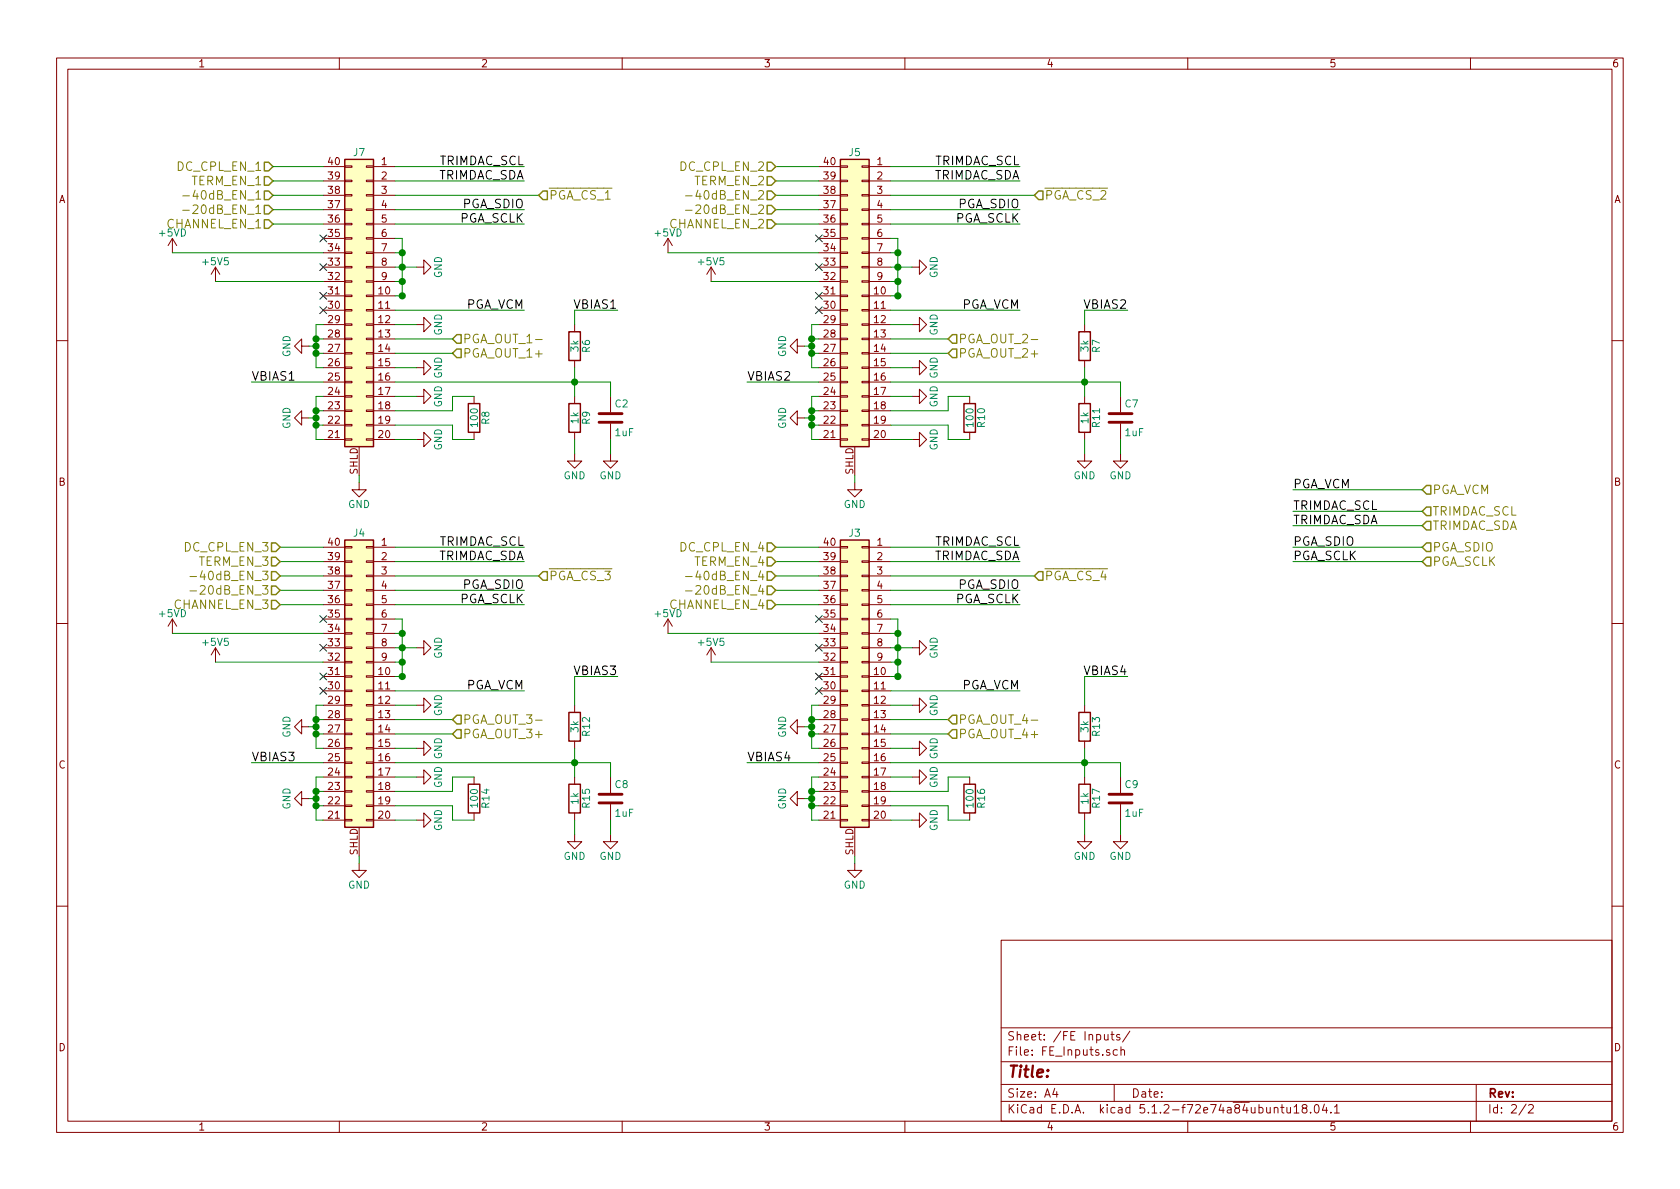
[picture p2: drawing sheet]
<svg xmlns="http://www.w3.org/2000/svg" width="297mm" height="210mm" viewBox="0 0 297 210" stroke-linecap="round" stroke-linejoin="round" font-family="sans-serif">
<defs><g id="words">
<text font-size="2.8" fill="#840000" x="178" y="190.5">Title:</text>
<g font-size="2.1">
<text x="77.5" y="29.2">TRIMDAC_SCL</text>
<text x="165.1" y="29.2">TRIMDAC_SCL</text>
<text x="77.3" y="31.7">TRIMDAC_SDA</text>
<text x="164.9" y="31.7">TRIMDAC_SDA</text>
<text x="81.2" y="39.4">PGA_SCLK</text>
<text x="81.7" y="36.8">PGA_SDIO</text>
<text x="168.8" y="39.4">PGA_SCLK</text>
<text x="169.4" y="36.8">PGA_SDIO</text>
<text x="82.2" y="54.6">PGA_VCM</text>
<text x="101.5" y="54.6">VBIAS1</text>
<text x="169.8" y="54.6">PGA_VCM</text>
<text x="191.7" y="54.6">VBIAS2</text>
<text x="44.4" y="67.3">VBIAS1</text>
<text x="132.1" y="67.3">VBIAS2</text>
<text x="228.6" y="86.4">PGA_VCM</text>
<text x="228.6" y="92.7">TRIMDAC_SDA</text>
<text x="228.6" y="90.2">TRIMDAC_SCL</text>
<text x="77.3" y="99.1">TRIMDAC_SDA</text>
<text x="77.5" y="96.5">TRIMDAC_SCL</text>
<text x="164.9" y="99.1">TRIMDAC_SDA</text>
<text x="165.1" y="96.5">TRIMDAC_SCL</text>
<text x="228.6" y="99.1">PGA_SCLK</text>
<text x="228.6" y="96.5">PGA_SDIO</text>
<text x="81.2" y="106.7">PGA_SCLK</text>
<text x="81.7" y="104.1">PGA_SDIO</text>
<text x="168.8" y="106.7">PGA_SCLK</text>
<text x="169.4" y="104.1">PGA_SDIO</text>
<text x="101.5" y="119.4">VBIAS3</text>
<text x="191.7" y="119.4">VBIAS4</text>
<text x="82.2" y="121.9">PGA_VCM</text>
<text x="169.8" y="121.9">PGA_VCM</text>
<text x="44.4" y="134.6">VBIAS3</text>
<text x="132.1" y="134.6">VBIAS4</text>
</g>
<g font-size="2.1" fill="#848400">
<text x="31.5" y="30.2">DC_CPL_EN_1</text>
<text x="34" y="32.8">TERM_EN_1</text>
<text x="34.1" y="35.3">-40dB_EN_1</text>
<text x="97" y="35.3">PGA_CS_1</text>
<text x="120.4" y="30.2">DC_CPL_EN_2</text>
<text x="122.9" y="32.8">TERM_EN_2</text>
<text x="123" y="35.3">-40dB_EN_2</text>
<text x="184.7" y="35.3">PGA_CS_2</text>
<text x="29.6" y="40.4">CHANNEL_EN_1</text>
<text x="34.1" y="37.8">-20dB_EN_1</text>
<text x="118.5" y="40.4">CHANNEL_EN_2</text>
<text x="123" y="37.8">-20dB_EN_2</text>
<text x="81.8" y="60.7">PGA_OUT_1-</text>
<text x="81.8" y="63.2">PGA_OUT_1+</text>
<text x="169.4" y="60.7">PGA_OUT_2-</text>
<text x="169.4" y="63.2">PGA_OUT_2+</text>
<text x="253.2" y="87.4">PGA_VCM</text>
<text x="253.2" y="91.2">TRIMDAC_SCL</text>
<text x="253.2" y="93.7">TRIMDAC_SDA</text>
<text x="32.8" y="97.5">DC_CPL_EN_3</text>
<text x="35.3" y="100.1">TERM_EN_3</text>
<text x="120.4" y="97.5">DC_CPL_EN_4</text>
<text x="122.9" y="100.1">TERM_EN_4</text>
<text x="253.2" y="97.5">PGA_SDIO</text>
<text x="253.2" y="100.1">PGA_SCLK</text>
<text x="30.9" y="107.7">CHANNEL_EN_3</text>
<text x="35.4" y="105.2">-20dB_EN_3</text>
<text x="35.4" y="102.6">-40dB_EN_3</text>
<text x="97" y="102.6">PGA_CS_3</text>
<text x="118.5" y="107.7">CHANNEL_EN_4</text>
<text x="123" y="105.2">-20dB_EN_4</text>
<text x="123" y="102.6">-40dB_EN_4</text>
<text x="184.7" y="102.6">PGA_CS_4</text>
<text x="81.8" y="128">PGA_OUT_3-</text>
<text x="81.8" y="130.6">PGA_OUT_3+</text>
<text x="169.4" y="128">PGA_OUT_4-</text>
<text x="169.4" y="130.6">PGA_OUT_4+</text>
</g>
<g font-size="2.1" fill="#840000">
<text x="178" y="184">Sheet: /FE Inputs/</text>
<text x="178" y="186.7">File: FE_Inputs.sch</text>
<text x="178" y="196.9">KiCad E.D.A. kicad 5.1.2-f72e74a84ubuntu18.04.1</text>
<text x="178" y="194.1">Size: A4</text>
<text x="200" y="194.1">Date:</text>
<text x="263" y="194.1">Rev:</text>
<text x="263" y="196.9">Id: 2/2</text>
</g>
<g font-size="1.8" fill="#840000">
<text x="35" y="11.9">1</text>
<text x="85" y="11.9">2</text>
<text x="135" y="11.9">3</text>
<text x="185" y="11.9">4</text>
<text x="235" y="11.9">5</text>
<text x="285" y="11.9">6</text>
<text x="58.1" y="29.2">40</text>
<text x="67.5" y="29.2">1</text>
<text x="145.7" y="29.2">40</text>
<text x="155.1" y="29.2">1</text>
<text x="10.4" y="35.9">A</text>
<text x="58.1" y="34.3">38</text>
<text x="58.1" y="31.7">39</text>
<text x="67.5" y="31.7">2</text>
<text x="67.5" y="34.3">3</text>
<text x="145.7" y="34.3">38</text>
<text x="145.7" y="31.7">39</text>
<text x="155.1" y="31.7">2</text>
<text x="155.1" y="34.3">3</text>
<text x="285.4" y="35.9">A</text>
<text x="58.1" y="41.9">35</text>
<text x="58.1" y="39.4">36</text>
<text x="58.1" y="36.8">37</text>
<text x="67.5" y="36.8">4</text>
<text x="67.5" y="39.4">5</text>
<text x="67.5" y="41.9">6</text>
<text x="145.7" y="41.9">35</text>
<text x="145.7" y="39.4">36</text>
<text x="145.7" y="36.8">37</text>
<text x="155.1" y="36.8">4</text>
<text x="155.1" y="39.4">5</text>
<text x="155.1" y="41.9">6</text>
<text x="58.1" y="47">33</text>
<text x="58.1" y="44.4">34</text>
<text x="67.5" y="44.4">7</text>
<text x="67.5" y="47">8</text>
<text x="145.7" y="47">33</text>
<text x="145.7" y="44.4">34</text>
<text x="155.1" y="44.4">7</text>
<text x="155.1" y="47">8</text>
<text x="58.1" y="52.1">31</text>
<text x="58.1" y="49.5">32</text>
<text x="67" y="52.1">10</text>
<text x="67.5" y="49.5">9</text>
<text x="145.7" y="52.1">31</text>
<text x="145.7" y="49.5">32</text>
<text x="154.6" y="52.1">10</text>
<text x="155.1" y="49.5">9</text>
<text x="58.1" y="59.7">28</text>
<text x="58.1" y="57.1">29</text>
<text x="58.1" y="54.6">30</text>
<text x="67" y="54.6">11</text>
<text x="67" y="57.1">12</text>
<text x="67" y="59.7">13</text>
<text x="145.7" y="59.7">28</text>
<text x="145.7" y="57.1">29</text>
<text x="145.7" y="54.6">30</text>
<text x="154.6" y="54.6">11</text>
<text x="154.6" y="57.1">12</text>
<text x="154.6" y="59.7">13</text>
<text x="58.1" y="64.8">26</text>
<text x="58.1" y="62.2">27</text>
<text x="67" y="62.2">14</text>
<text x="67" y="64.8">15</text>
<text x="145.7" y="64.8">26</text>
<text x="145.7" y="62.2">27</text>
<text x="154.6" y="62.2">14</text>
<text x="154.6" y="64.8">15</text>
<text x="58.1" y="69.8">24</text>
<text x="58.1" y="67.3">25</text>
<text x="67" y="67.3">16</text>
<text x="67" y="69.8">17</text>
<text x="145.7" y="69.8">24</text>
<text x="145.7" y="67.3">25</text>
<text x="154.6" y="67.3">16</text>
<text x="154.6" y="69.8">17</text>
<text x="58.1" y="77.5">21</text>
<text x="58.1" y="74.9">22</text>
<text x="58.1" y="72.4">23</text>
<text x="67" y="72.4">18</text>
<text x="67" y="74.9">19</text>
<text x="67" y="77.5">20</text>
<text x="145.7" y="77.5">21</text>
<text x="145.7" y="74.9">22</text>
<text x="145.7" y="72.4">23</text>
<text x="154.6" y="72.4">18</text>
<text x="154.6" y="74.9">19</text>
<text x="154.6" y="77.5">20</text>
<text x="63.2" y="83.9" transform="rotate(-90 63.2 83.9)">SHLD</text>
<text x="150.9" y="83.9" transform="rotate(-90 150.9 83.9)">SHLD</text>
<text x="10.4" y="85.9">B</text>
<text x="285.4" y="85.9">B</text>
<text x="58.1" y="101.6">38</text>
<text x="58.1" y="99.1">39</text>
<text x="58.1" y="96.5">40</text>
<text x="67.5" y="96.5">1</text>
<text x="67.5" y="99.1">2</text>
<text x="67.5" y="101.6">3</text>
<text x="145.7" y="101.6">38</text>
<text x="145.7" y="99.1">39</text>
<text x="145.7" y="96.5">40</text>
<text x="155.1" y="96.5">1</text>
<text x="155.1" y="99.1">2</text>
<text x="155.1" y="101.6">3</text>
<text x="58.1" y="106.7">36</text>
<text x="58.1" y="104.1">37</text>
<text x="67.5" y="104.1">4</text>
<text x="67.5" y="106.7">5</text>
<text x="145.7" y="106.7">36</text>
<text x="145.7" y="104.1">37</text>
<text x="155.1" y="104.1">4</text>
<text x="155.1" y="106.7">5</text>
<text x="58.1" y="111.8">34</text>
<text x="58.1" y="109.2">35</text>
<text x="67.5" y="109.2">6</text>
<text x="67.5" y="111.8">7</text>
<text x="145.7" y="111.8">34</text>
<text x="145.7" y="109.2">35</text>
<text x="155.1" y="109.2">6</text>
<text x="155.1" y="111.8">7</text>
<text x="58.1" y="119.4">31</text>
<text x="58.1" y="116.8">32</text>
<text x="58.1" y="114.3">33</text>
<text x="67" y="119.4">10</text>
<text x="67.5" y="114.3">8</text>
<text x="67.5" y="116.8">9</text>
<text x="145.7" y="119.4">31</text>
<text x="145.7" y="116.8">32</text>
<text x="145.7" y="114.3">33</text>
<text x="154.6" y="119.4">10</text>
<text x="155.1" y="114.3">8</text>
<text x="155.1" y="116.8">9</text>
<text x="58.1" y="124.5">29</text>
<text x="58.1" y="121.9">30</text>
<text x="67" y="121.9">11</text>
<text x="67" y="124.5">12</text>
<text x="145.7" y="124.5">29</text>
<text x="145.7" y="121.9">30</text>
<text x="154.6" y="121.9">11</text>
<text x="154.6" y="124.5">12</text>
<text x="58.1" y="129.5">27</text>
<text x="58.1" y="127">28</text>
<text x="67" y="127">13</text>
<text x="67" y="129.5">14</text>
<text x="145.7" y="129.5">27</text>
<text x="145.7" y="127">28</text>
<text x="154.6" y="127">13</text>
<text x="154.6" y="129.5">14</text>
<text x="10.4" y="135.9">C</text>
<text x="58.1" y="137.2">24</text>
<text x="58.1" y="134.6">25</text>
<text x="58.1" y="132.1">26</text>
<text x="67" y="132.1">15</text>
<text x="67" y="134.6">16</text>
<text x="67" y="137.2">17</text>
<text x="145.7" y="137.2">24</text>
<text x="145.7" y="134.6">25</text>
<text x="145.7" y="132.1">26</text>
<text x="154.6" y="132.1">15</text>
<text x="154.6" y="134.6">16</text>
<text x="154.6" y="137.2">17</text>
<text x="285.4" y="135.9">C</text>
<text x="58.1" y="142.2">22</text>
<text x="58.1" y="139.7">23</text>
<text x="67" y="139.7">18</text>
<text x="67" y="142.2">19</text>
<text x="145.7" y="142.2">22</text>
<text x="145.7" y="139.7">23</text>
<text x="154.6" y="139.7">18</text>
<text x="154.6" y="142.2">19</text>
<text x="58.1" y="144.8">21</text>
<text x="67" y="144.8">20</text>
<text x="145.7" y="144.8">21</text>
<text x="154.6" y="144.8">20</text>
<text x="63.2" y="151.3" transform="rotate(-90 63.2 151.3)">SHLD</text>
<text x="150.9" y="151.3" transform="rotate(-90 150.9 151.3)">SHLD</text>
<text x="10.4" y="185.9">D</text>
<text x="285.4" y="185.9">D</text>
<text x="35" y="199.9">1</text>
<text x="85" y="199.9">2</text>
<text x="135" y="199.9">3</text>
<text x="185" y="199.9">4</text>
<text x="235" y="199.9">5</text>
<text x="285" y="199.9">6</text>
</g>
<g font-size="1.8" fill="#008484">
<text x="62.5" y="27.6">J7</text>
<text x="150.2" y="27.6">J5</text>
<text x="28.2" y="41.8">+5VD</text>
<text x="115.9" y="41.8">+5VD</text>
<text x="36" y="46.9">+5V5</text>
<text x="123.6" y="46.9">+5V5</text>
<text x="78.2" y="49.2" transform="rotate(-90 78.2 49.2)">GND</text>
<text x="165.8" y="49.2" transform="rotate(-90 165.8 49.2)">GND</text>
<text x="78.2" y="59.4" transform="rotate(-90 78.2 59.4)">GND</text>
<text x="165.8" y="59.4" transform="rotate(-90 165.8 59.4)">GND</text>
<text x="51.4" y="63.2" transform="rotate(-90 51.4 63.2)">GND</text>
<text x="102.3" y="62.2" transform="rotate(-90 102.3 62.2)">3k</text>
<text x="104.3" y="62.3" transform="rotate(-90 104.3 62.3)">R6</text>
<text x="139" y="63.2" transform="rotate(-90 139 63.2)">GND</text>
<text x="192.5" y="62.2" transform="rotate(-90 192.5 62.2)">3k</text>
<text x="194.5" y="62.3" transform="rotate(-90 194.5 62.3)">R7</text>
<text x="78.2" y="67" transform="rotate(-90 78.2 67)">GND</text>
<text x="165.8" y="67" transform="rotate(-90 165.8 67)">GND</text>
<text x="51.4" y="75.9" transform="rotate(-90 51.4 75.9)">GND</text>
<text x="78.2" y="72.1" transform="rotate(-90 78.2 72.1)">GND</text>
<text x="84.5" y="75.4" transform="rotate(-90 84.5 75.4)">100</text>
<text x="86.5" y="75" transform="rotate(-90 86.5 75)">R8</text>
<text x="102.3" y="74.9" transform="rotate(-90 102.3 74.9)">1k</text>
<text x="104.3" y="75" transform="rotate(-90 104.3 75)">R9</text>
<text x="108.8" y="72.1">C2</text>
<text x="108.8" y="77.1">1uF</text>
<text x="139" y="75.9" transform="rotate(-90 139 75.9)">GND</text>
<text x="165.8" y="72.1" transform="rotate(-90 165.8 72.1)">GND</text>
<text x="172.1" y="75.4" transform="rotate(-90 172.1 75.4)">100</text>
<text x="174.2" y="75.5" transform="rotate(-90 174.2 75.5)">R10</text>
<text x="192.5" y="74.9" transform="rotate(-90 192.5 74.9)">1k</text>
<text x="194.5" y="75.5" transform="rotate(-90 194.5 75.5)">R11</text>
<text x="199" y="72.1">C7</text>
<text x="199" y="77.1">1uF</text>
<text x="78.2" y="79.7" transform="rotate(-90 78.2 79.7)">GND</text>
<text x="165.8" y="79.7" transform="rotate(-90 165.8 79.7)">GND</text>
<text x="61.5" y="89.8">GND</text>
<text x="99.6" y="84.8">GND</text>
<text x="106" y="84.8">GND</text>
<text x="149.2" y="89.8">GND</text>
<text x="189.8" y="84.8">GND</text>
<text x="196.2" y="84.8">GND</text>
<text x="62.5" y="94.9">J4</text>
<text x="150.2" y="94.9">J3</text>
<text x="28.2" y="109.1">+5VD</text>
<text x="115.9" y="109.1">+5VD</text>
<text x="36" y="114.2">+5V5</text>
<text x="78.2" y="116.5" transform="rotate(-90 78.2 116.5)">GND</text>
<text x="123.6" y="114.2">+5V5</text>
<text x="165.8" y="116.5" transform="rotate(-90 165.8 116.5)">GND</text>
<text x="51.4" y="130.5" transform="rotate(-90 51.4 130.5)">GND</text>
<text x="78.2" y="126.7" transform="rotate(-90 78.2 126.7)">GND</text>
<text x="102.3" y="129.5" transform="rotate(-90 102.3 129.5)">3k</text>
<text x="104.3" y="130.1" transform="rotate(-90 104.3 130.1)">R12</text>
<text x="139" y="130.5" transform="rotate(-90 139 130.5)">GND</text>
<text x="165.8" y="126.7" transform="rotate(-90 165.8 126.7)">GND</text>
<text x="192.5" y="129.5" transform="rotate(-90 192.5 129.5)">3k</text>
<text x="194.5" y="130.1" transform="rotate(-90 194.5 130.1)">R13</text>
<text x="78.2" y="134.3" transform="rotate(-90 78.2 134.3)">GND</text>
<text x="165.8" y="134.3" transform="rotate(-90 165.8 134.3)">GND</text>
<text x="51.4" y="143.2" transform="rotate(-90 51.4 143.2)">GND</text>
<text x="78.2" y="139.4" transform="rotate(-90 78.2 139.4)">GND</text>
<text x="84.5" y="142.7" transform="rotate(-90 84.5 142.7)">100</text>
<text x="86.5" y="142.8" transform="rotate(-90 86.5 142.8)">R14</text>
<text x="102.3" y="142.2" transform="rotate(-90 102.3 142.2)">1k</text>
<text x="104.3" y="142.8" transform="rotate(-90 104.3 142.8)">R15</text>
<text x="108.8" y="139.4">C8</text>
<text x="139" y="143.2" transform="rotate(-90 139 143.2)">GND</text>
<text x="165.8" y="139.4" transform="rotate(-90 165.8 139.4)">GND</text>
<text x="172.1" y="142.7" transform="rotate(-90 172.1 142.7)">100</text>
<text x="174.2" y="142.8" transform="rotate(-90 174.2 142.8)">R16</text>
<text x="192.5" y="142.2" transform="rotate(-90 192.5 142.2)">1k</text>
<text x="194.5" y="142.8" transform="rotate(-90 194.5 142.8)">R17</text>
<text x="199" y="139.4">C9</text>
<text x="78.2" y="147" transform="rotate(-90 78.2 147)">GND</text>
<text x="108.8" y="144.4">1uF</text>
<text x="165.8" y="147" transform="rotate(-90 165.8 147)">GND</text>
<text x="199" y="144.4">1uF</text>
<text x="99.6" y="152.1">GND</text>
<text x="106" y="152.1">GND</text>
<text x="189.8" y="152.1">GND</text>
<text x="196.2" y="152.1">GND</text>
<text x="61.5" y="157.1">GND</text>
<text x="149.2" y="157.1">GND</text>
</g>
</g></defs>
<g fill="none" stroke="#840000" stroke-width=".18">
<path d="M10 10.3h277v189.9h-277zM12 12.2h273v186.1h-273zM60 10.3v1.9M110 10.3v1.9M160 10.3v1.9M210 10.3v1.9M260 10.3v1.9M57.1 29.5h3.9M57.1 32h3.9M57.1 34.5h3.9M57.1 39.6h3.9M57.1 37.1h3.9"/>
<path d="M61 39.5h1.2v.2h-1.2zM61 37h1.2v.2h-1.2zM61 34.4h1.2v.3h-1.2zM61 31.9h1.2v.2h-1.2zM61 29.3h1.2v.3h-1.2zM64.8 39.5h1.2v.2h-1.2zM64.8 37h1.2v.2h-1.2zM64.8 34.4h1.2v.3h-1.2zM64.8 31.9h1.2v.2h-1.2zM64.8 29.3h1.2v.3h-1.2zM66 29.5h3.8M66 32h3.8"/>
<path d="M66 34.5h3.8M66 39.6h3.8M66 37.1h3.8M144.8 29.5h3.8M144.8 32h3.8M144.8 34.5h3.8M144.8 39.6h3.8M144.8 37.1h3.8M148.6 39.5h1.3v.2h-1.3zM148.6 37h1.3v.2h-1.3zM148.6 34.4h1.3v.3h-1.3zM148.6 31.9h1.3v.2h-1.3z"/>
<path d="M148.6 29.3h1.3v.3h-1.3zM152.4 39.5h1.3v.2h-1.3zM152.4 37h1.3v.2h-1.3zM152.4 34.4h1.3v.3h-1.3zM152.4 31.9h1.3v.2h-1.3zM152.4 29.3h1.3v.3h-1.3zM153.7 29.5h3.8M153.7 32h3.8M153.7 34.5h3.8M153.7 39.6h3.8M153.7 37.1h3.8M30.5 42.2l.7 1.2"/>
<path d="M30.5 42.2v2.5M30.5 42.2l-.8 1.2M38.1 47.2l.8 1.3M38.1 47.2v2.6M38.1 47.2l-.8 1.3M57.1 52.3h3.9M57.1 54.9h3.9M57.1 57.4h3.9M57.1 59.9h3.9M57.1 49.8h3.9M57.1 47.2h3.9M57.1 44.7h3.9"/>
<path d="M57.1 42.2h3.9M61 59.8h1.2v.3h-1.2zM61 57.3h1.2v.2h-1.2zM61 54.7h1.2v.3h-1.2zM61 52.2h1.2v.2h-1.2zM61 49.7h1.2v.2h-1.2zM61 47.1h1.2v.3h-1.2zM61 44.6h1.2v.2h-1.2zM61 42h1.2v.3h-1.2zM64.8 59.8h1.2v.3h-1.2zM64.8 57.3h1.2v.2h-1.2zM64.8 54.7h1.2v.3h-1.2z"/>
<path d="M64.8 52.2h1.2v.2h-1.2zM64.8 49.7h1.2v.2h-1.2zM64.8 47.1h1.2v.3h-1.2zM64.8 44.6h1.2v.2h-1.2zM64.8 42h1.2v.3h-1.2zM66 52.3h3.8M66 54.9h3.8M66 57.4h3.8M66 59.9h3.8M66 49.8h3.8M66 47.2h3.8M66 44.7h3.8"/>
<path d="M66 42.2h3.8M73.7 57.4h1.2v1.3l1.3-1.3-1.3-1.3v1.3M73.7 47.2h1.2v1.3l1.3-1.3-1.3-1.2v1.2M101.6 57.4v1.3M118.1 42.2l.8 1.2M118.1 42.2v2.5M118.1 42.2l-.8 1.2M125.7 47.2l.8 1.3M125.7 47.2v2.6M125.7 47.2l-.7 1.3M144.8 52.3h3.8M144.8 54.9h3.8"/>
<path d="M144.8 57.4h3.8M144.8 59.9h3.8M144.8 49.8h3.8M144.8 47.2h3.8M144.8 44.7h3.8M144.8 42.2h3.8M148.6 59.8h1.3v.3h-1.3zM148.6 57.3h1.3v.2h-1.3zM148.6 54.7h1.3v.3h-1.3zM148.6 52.2h1.3v.2h-1.3zM148.6 49.7h1.3v.2h-1.3zM148.6 47.1h1.3v.3h-1.3z"/>
<path d="M148.6 44.6h1.3v.2h-1.3zM148.6 42h1.3v.3h-1.3zM152.4 59.8h1.3v.3h-1.3zM152.4 57.3h1.3v.2h-1.3zM152.4 54.7h1.3v.3h-1.3zM152.4 52.2h1.3v.2h-1.3zM152.4 49.7h1.3v.2h-1.3zM152.4 47.1h1.3v.3h-1.3zM152.4 44.6h1.3v.2h-1.3zM152.4 42h1.3v.3h-1.3zM153.7 52.3h3.8M153.7 54.9h3.8"/>
<path d="M153.7 57.4h3.8M153.7 59.9h3.8M153.7 49.8h3.8M153.7 47.2h3.8M153.7 44.7h3.8M153.7 42.2h3.8M161.3 57.4h1.3v1.3l1.2-1.3-1.2-1.3v1.3M161.3 47.2h1.3v1.3l1.2-1.3-1.2-1.2v1.2M191.8 57.4v1.3M10 60.2h2M53.3 73.9v1.3l-1.2-1.3 1.2-1.3v1.3h1.3M53.3 61.2v1.3l-1.2-1.3 1.2-1.3v1.3h1.3"/>
<path d="M57.1 62.5h3.9M57.1 65h3.9M57.1 67.6h3.9M57.1 70.1h3.9M57.1 72.6h3.9M57.1 75.2h3.9M57.1 77.7h3.9M61 77.6h1.2v.2h-1.2zM61 75.1h1.2v.2h-1.2zM61 72.5h1.2v.3h-1.2zM61 70h1.2v.2h-1.2zM61 67.4h1.2v.3h-1.2z"/>
<path d="M61 64.9h1.2v.2h-1.2zM61 62.4h1.2v.2h-1.2zM63.5 79v5.1M64.8 77.6h1.2v.2h-1.2zM64.8 75.1h1.2v.2h-1.2zM64.8 72.5h1.2v.3h-1.2zM64.8 70h1.2v.2h-1.2zM64.8 67.4h1.2v.3h-1.2zM64.8 64.9h1.2v.2h-1.2zM64.8 62.4h1.2v.2h-1.2zM66 62.5h3.8M66 65h3.8"/>
<path d="M66 67.6h3.8M66 70.1h3.8M66 72.6h3.8M66 75.2h3.8M66 77.7h3.8M73.7 77.7h1.2v1.3l1.3-1.3-1.3-1.3v1.3M73.7 70.1h1.2v1.3l1.3-1.3-1.3-1.3v1.3M73.7 65h1.2v1.3l1.3-1.3-1.3-1.3v1.3M83.8 70.1v1.3M83.8 76.4v1.3M101.6 63.7v1.3M101.6 70.1v1.3"/>
<path d="M101.6 76.4v1.3M107.9 70.1v2.8M107.9 74.9v2.8M141 73.9v1.3l-1.3-1.3 1.3-1.3v1.3h1.2M141 61.2v1.3l-1.3-1.3 1.3-1.3v1.3h1.2M144.8 62.5h3.8M144.8 65h3.8M144.8 67.6h3.8M144.8 70.1h3.8M144.8 72.6h3.8M144.8 75.2h3.8M144.8 77.7h3.8"/>
<path d="M148.6 77.6h1.3v.2h-1.3zM148.6 75.1h1.3v.2h-1.3zM148.6 72.5h1.3v.3h-1.3zM148.6 70h1.3v.2h-1.3zM148.6 67.4h1.3v.3h-1.3zM148.6 64.9h1.3v.2h-1.3zM148.6 62.4h1.3v.2h-1.3zM151.1 79v5.1M152.4 77.6h1.3v.2h-1.3zM152.4 75.1h1.3v.2h-1.3zM152.4 72.5h1.3v.3h-1.3zM152.4 70h1.3v.2h-1.3z"/>
<path d="M152.4 67.4h1.3v.3h-1.3zM152.4 64.9h1.3v.2h-1.3zM152.4 62.4h1.3v.2h-1.3zM153.7 62.5h3.8M153.7 65h3.8M153.7 67.6h3.8M153.7 70.1h3.8M153.7 72.6h3.8M153.7 75.2h3.8M153.7 77.7h3.8M161.3 77.7h1.3v1.3l1.2-1.3-1.2-1.3v1.3M161.3 70.1h1.3v1.3l1.2-1.3-1.2-1.3v1.3"/>
<path d="M161.3 65h1.3v1.3l1.2-1.3-1.2-1.3v1.3M171.4 70.1v1.3M171.4 76.4v1.3M191.8 63.7v1.3M191.8 70.1v1.3M191.8 76.4v1.3M198.1 70.1v2.8M198.1 74.9v2.8M285 60.2h2M57.1 96.8h3.9M57.1 99.3h3.9M61 99.2h1.2v.2h-1.2z"/>
<path d="M61 96.6h1.2v.3h-1.2zM63.5 85.3v1.3h-1.3l1.3 1.3 1.3-1.3h-1.3M64.8 99.2h1.2v.2h-1.2zM64.8 96.6h1.2v.3h-1.2zM66 96.8h3.8M66 99.3h3.8M101.6 80.3v1.2h1.3l-1.3 1.3-1.3-1.3h1.3M107.9 80.3v1.2h1.3l-1.3 1.3-1.2-1.3h1.2M144.8 96.8h3.8M144.8 99.3h3.8M148.6 99.2h1.3v.2h-1.3zM148.6 96.6h1.3v.3h-1.3z"/>
<path d="M151.1 85.3v1.3h-1.2l1.2 1.3 1.3-1.3h-1.3M152.4 99.2h1.3v.2h-1.3zM152.4 96.6h1.3v.3h-1.3zM153.7 96.8h3.8M153.7 99.3h3.8M191.8 80.3v1.2h1.2l-1.2 1.3-1.3-1.3h1.3M198.1 80.3v1.2h1.3l-1.3 1.3-1.3-1.3h1.3M10 110.3h2M30.5 109.5v2.5M30.5 109.5l.7 1.2M30.5 109.5l-.8 1.2M38.1 114.5v2.6"/>
<path d="M38.1 114.5l.8 1.3M38.1 114.5l-.8 1.3M57.1 119.6h3.9M57.1 101.8h3.9M57.1 117.1h3.9M57.1 114.5h3.9M57.1 112h3.9M57.1 109.5h3.9M57.1 106.9h3.9M57.1 104.4h3.9M61 119.5h1.2v.3h-1.2zM61 117h1.2v.2h-1.2z"/>
<path d="M61 114.4h1.2v.3h-1.2zM61 111.9h1.2v.2h-1.2zM61 109.3h1.2v.3h-1.2zM61 106.8h1.2v.3h-1.2zM61 104.3h1.2v.2h-1.2zM61 101.7h1.2v.3h-1.2zM64.8 119.5h1.2v.3h-1.2zM64.8 117h1.2v.2h-1.2zM64.8 114.4h1.2v.3h-1.2zM64.8 111.9h1.2v.2h-1.2zM64.8 109.3h1.2v.3h-1.2zM64.8 106.8h1.2v.3h-1.2z"/>
<path d="M64.8 104.3h1.2v.2h-1.2zM64.8 101.7h1.2v.3h-1.2zM66 119.6h3.8M66 101.8h3.8M66 117.1h3.8M66 114.5h3.8M66 112h3.8M66 109.5h3.8M66 106.9h3.8M66 104.4h3.8M73.7 114.5h1.2v1.3l1.3-1.3-1.3-1.2v1.2M118.1 109.5v2.5"/>
<path d="M118.1 109.5l.8 1.2M118.1 109.5l-.8 1.2M125.7 114.5v2.6M125.7 114.5l.8 1.3M125.7 114.5l-.7 1.3M144.8 119.6h3.8M144.8 101.8h3.8M144.8 117.1h3.8M144.8 114.5h3.8M144.8 112h3.8M144.8 109.5h3.8M144.8 106.9h3.8"/>
<path d="M144.8 104.4h3.8M148.6 119.5h1.3v.3h-1.3zM148.6 117h1.3v.2h-1.3zM148.6 114.4h1.3v.3h-1.3zM148.6 111.9h1.3v.2h-1.3zM148.6 109.3h1.3v.3h-1.3zM148.6 106.8h1.3v.3h-1.3zM148.6 104.3h1.3v.2h-1.3zM148.6 101.7h1.3v.3h-1.3zM152.4 119.5h1.3v.3h-1.3zM152.4 117h1.3v.2h-1.3zM152.4 114.4h1.3v.3h-1.3z"/>
<path d="M152.4 111.9h1.3v.2h-1.3zM152.4 109.3h1.3v.3h-1.3zM152.4 106.8h1.3v.3h-1.3zM152.4 104.3h1.3v.2h-1.3zM152.4 101.7h1.3v.3h-1.3zM153.7 119.6h3.8M153.7 101.8h3.8M153.7 117.1h3.8M153.7 114.5h3.8M153.7 112h3.8M153.7 109.5h3.8M153.7 106.9h3.8"/>
<path d="M153.7 104.4h3.8M161.3 114.5h1.3v1.3l1.2-1.3-1.2-1.2v1.2M285 110.3h2M53.3 128.5v1.3l-1.2-1.3 1.2-1.3v1.3h1.3M57.1 122.2h3.9M57.1 124.7h3.9M57.1 127.2h3.9M57.1 129.8h3.9M57.1 132.3h3.9M57.1 134.9h3.9M57.1 137.4h3.9M57.1 139.9h3.9"/>
<path d="M61 139.8h1.2v.3h-1.2zM61 137.3h1.2v.2h-1.2zM61 134.7h1.2v.3h-1.2zM61 132.2h1.2v.3h-1.2zM61 129.7h1.2v.2h-1.2zM61 127.1h1.2v.3h-1.2zM61 124.6h1.2v.2h-1.2zM61 122h1.2v.3h-1.2zM64.8 139.8h1.2v.3h-1.2zM64.8 137.3h1.2v.2h-1.2zM64.8 134.7h1.2v.3h-1.2zM64.8 132.2h1.2v.3h-1.2z"/>
<path d="M64.8 129.7h1.2v.2h-1.2zM64.8 127.1h1.2v.3h-1.2zM64.8 124.6h1.2v.2h-1.2zM64.8 122h1.2v.3h-1.2zM66 122.2h3.8M66 124.7h3.8M66 127.2h3.8M66 129.8h3.8M66 132.3h3.8M66 134.9h3.8M66 137.4h3.8M66 139.9h3.8"/>
<path d="M73.7 137.4h1.2v1.3l1.3-1.3-1.3-1.3v1.3M73.7 132.3h1.2v1.3l1.3-1.3-1.3-1.2v1.2M73.7 124.7h1.2v1.3l1.3-1.3-1.3-1.3v1.3M83.8 137.4v1.3M101.6 124.7v1.3M101.6 131.1v1.2M101.6 137.4v1.3M107.9 137.4v2.8M141 128.5v1.3l-1.3-1.3 1.3-1.3v1.3h1.2M144.8 122.2h3.8M144.8 124.7h3.8M144.8 127.2h3.8"/>
<path d="M144.8 129.8h3.8M144.8 132.3h3.8M144.8 134.9h3.8M144.8 137.4h3.8M144.8 139.9h3.8M148.6 139.8h1.3v.3h-1.3zM148.6 137.3h1.3v.2h-1.3zM148.6 134.7h1.3v.3h-1.3zM148.6 132.2h1.3v.3h-1.3zM148.6 129.7h1.3v.2h-1.3zM148.6 127.1h1.3v.3h-1.3zM148.6 124.6h1.3v.2h-1.3z"/>
<path d="M148.6 122h1.3v.3h-1.3zM152.4 139.8h1.3v.3h-1.3zM152.4 137.3h1.3v.2h-1.3zM152.4 134.7h1.3v.3h-1.3zM152.4 132.2h1.3v.3h-1.3zM152.4 129.7h1.3v.2h-1.3zM152.4 127.1h1.3v.3h-1.3zM152.4 124.6h1.3v.2h-1.3zM152.4 122h1.3v.3h-1.3zM153.7 122.2h3.8M153.7 124.7h3.8M153.7 127.2h3.8"/>
<path d="M153.7 129.8h3.8M153.7 132.3h3.8M153.7 134.9h3.8M153.7 137.4h3.8M153.7 139.9h3.8M161.3 137.4h1.3v1.3l1.2-1.3-1.2-1.3v1.3M161.3 132.3h1.3v1.3l1.2-1.3-1.2-1.2v1.2M161.3 124.7h1.3v1.3l1.2-1.3-1.2-1.3v1.3M171.4 137.4v1.3M191.8 124.7v1.3M191.8 131.1v1.2M191.8 137.4v1.3"/>
<path d="M198.1 137.4v2.8M53.3 141.2v1.3l-1.2-1.3 1.2-1.3v1.3h1.3M57.1 142.5h3.9M57.1 145h3.9M61 144.9h1.2v.3h-1.2zM61 142.4h1.2v.2h-1.2zM63.5 152.6v1.3h-1.3l1.3 1.3 1.3-1.3h-1.3M63.5 146.3v5.1M64.8 144.9h1.2v.3h-1.2zM64.8 142.4h1.2v.2h-1.2zM66 142.5h3.8M66 145h3.8"/>
<path d="M73.7 145h1.2v1.3l1.3-1.3-1.3-1.2v1.2M83.8 143.8v1.2M101.6 147.6v1.2h1.3l-1.3 1.3-1.3-1.3h1.3M101.6 143.8v1.2M107.9 147.6v1.2h1.3l-1.3 1.3-1.2-1.3h1.2M107.9 142.2v2.8M141 141.2v1.3l-1.3-1.3 1.3-1.3v1.3h1.2M144.8 142.5h3.8M144.8 145h3.8M148.6 144.9h1.3v.3h-1.3zM148.6 142.4h1.3v.2h-1.3zM151.1 152.6v1.3h-1.2l1.2 1.3 1.3-1.3h-1.3"/>
<path d="M151.1 146.3v5.1M152.4 144.9h1.3v.3h-1.3zM152.4 142.4h1.3v.2h-1.3zM153.7 142.5h3.8M153.7 145h3.8M161.3 145h1.3v1.3l1.2-1.3-1.2-1.2v1.2M171.4 143.8v1.2M191.8 147.6v1.2h1.2l-1.2 1.3-1.3-1.3h1.3M191.8 143.8v1.2M198.1 147.6v1.2h1.3l-1.3 1.3-1.3-1.3h1.3M198.1 142.2v2.8M10 160.2h2"/>
<path d="M177 166.3h108v32h-108zM285 160.2h2M60 198.3v1.9M110 198.3v1.9M160 198.3v1.9M177 194.8h108M177 191.8h108M177 187.8h108M177 181.8h108M186.5 192.5l-.4 1h1M186.8 193v1M195.3 182.9v.9l.4 .1 .2-.1"/>
<path d="M195.9 182.9v1M196.4 182.9h.6M196.6 182.4v1.3l.4 .2M197 191.8v3M197.6 185.7l-.5-.1-.3 .3 .1 .6 .2 .1 .5-.1M198 183l-.4-.1-.2 .2 .1 .3 .5 .1v.3h-.6M198.2 185.7l.2-.1 .4 .1v.9M198.2 185.1v1.5M199.8 182.3l-1.3 2M210 198.3v1.9M225.3 196l.1-.1a.37 .37 0 0 1 .6 .1v.8M226.4 195.8h.6"/>
<path d="M226.7 195.3v1.3l.3 .2M227.5 195.8l.1 .9 .3 .1 .3-.1M228.2 195.8v1M228.8 195.8l.4-.5v1.5M228.8 196.8h.9M230.5 196l-.2-.2-.1-.2 .3-.3h.3l.3 .3-.1 .2-.6 .2a.48 .48 0 0 0-.1 .7l.2 .1 .5-.1a.48 .48 0 0 0-.2-.7M231.7 196.7v.1M232.5 195.5l.4-.2a.94 .94 0 0 1 0 1.5l-.5-.3v-.6zM234.2 195.2l-.4 1.1h.9M234.5 195.8v1M235.3 196.7v.1M235.9 195.8l.5-.5v1.5"/>
<path d="M235.9 196.8h.9M260 198.3v1.9M261 191.8v6.5M269.8 195.2l-1.2 2M270.3 195.5l.2-.2h.3l.3 .5-.9 1h.9"/>
</g>
<g fill="#ffffc2" stroke="#ffffc2" stroke-width=".18">
<path d="M148.6 95.5h5.1v50.8h-5.1z"/>
<path d="M148.6 28.2h5.1v50.8h-5.1z"/>
<path d="M61 95.5h5v50.8h-5z"/>
<path d="M61 28.2h5v50.8h-5z"/>
</g>
<g fill="none" stroke="#840000" stroke-width=".25">
<path d="M61 28.2h5v50.8h-5zM148.6 28.2h5.1v50.8h-5.1zM100.6 58.7h2v5h-2zM190.8 58.7h2v5h-2zM82.8 71.4h2v5h-2zM100.6 71.4h2v5h-2zM170.4 71.4h2.1v5h-2.1zM190.8 71.4h2v5h-2zM61 95.5h5v50.8h-5zM148.6 95.5h5.1v50.8h-5.1zM82.8 138.7h2v5.1h-2zM100.6 126h2v5.1h-2z"/>
<path d="M100.6 138.7h2v5.1h-2zM170.4 138.7h2.1v5.1h-2.1zM190.8 126h2v5.1h-2zM190.8 138.7h2v5.1h-2z"/>
</g>
<path d="M105.9 74.7h4.1M105.9 73.1h4.1M196.1 74.7h4.1M196.1 73.1h4.1M105.9 142h4.1M105.9 140.5h4.1M196.1 142h4.1M196.1 140.5h4.1" fill="none" stroke="#840000" stroke-width=".51"/>
<g fill="none" stroke="#000084" stroke-width=".18">
<path d="M56.5 54.2l1.3 1.3M56.5 41.5l1.3 1.3M56.5 46.6l1.3 1.2M56.5 51.7l1.3 1.2M57.8 54.2l-1.3 1.3M57.8 41.5l-1.3 1.3M57.8 46.6l-1.3 1.2M57.8 51.7l-1.3 1.2M144.2 54.2l1.2 1.3M144.2 51.7l1.2 1.2M144.2 46.6l1.2 1.2M144.2 41.5l1.2 1.3"/>
<path d="M145.4 54.2l-1.2 1.3M145.4 51.7l-1.2 1.2M145.4 46.6l-1.2 1.2M145.4 41.5l-1.2 1.3M56.5 119l1.3 1.2M56.5 113.9l1.3 1.3M56.5 108.9l1.3 1.2M57.8 119l-1.3 1.2M57.8 113.9l-1.3 1.3M57.8 108.9l-1.3 1.2M144.2 119l1.2 1.2M144.2 113.9l1.2 1.3"/>
<path d="M144.2 108.9l1.2 1.2M145.4 119l-1.2 1.2M145.4 113.9l-1.2 1.3M145.4 108.9l-1.2 1.2M56.5 121.6l1.3 1.2M57.8 121.6l-1.3 1.2M144.2 121.6l1.2 1.2M145.4 121.6l-1.2 1.2"/>
</g>
<path d="M32.3 37.2h1.2M32.3 34.6h1.2M121.2 37.2h1.2M121.2 34.6h1.2M94.7 60h1.2M182.3 60h1.2M33.6 104.5h1.1M33.6 101.9h1.1M121.2 104.5h1.2M121.2 101.9h1.2M94.7 127.3h1.2M182.3 127.3h1.2" fill="none" stroke="#848400" stroke-width=".18"/>
<g fill="none" stroke="#848400" stroke-width=".25">
<path d="M46.7 36.3h.8l.8 .8-.8 .7h-.8zM46.7 38.9h.8l.8 .7-.8 .8h-.8zM46.7 33.8h.8l.8 .7-.8 .8h-.8zM46.7 31.2h.8l.8 .8-.8 .8h-.8zM46.7 28.7h.8l.8 .8-.8 .7h-.8zM96 33.8h.8v1.5h-.8l-.8-.8zM135.6 36.3h.8l.8 .8-.8 .7h-.8zM135.6 38.9h.8l.8 .7-.8 .8h-.8zM135.6 33.8h.8l.8 .7-.8 .8h-.8zM135.6 31.2h.8l.8 .8-.8 .8h-.8zM135.6 28.7h.8l.8 .8-.8 .7h-.8zM183.6 33.8h.8v1.5h-.8l-.7-.8z"/>
<path d="M80.8 59.2h.7v1.5h-.7l-.8-.8zM167.6 59.9l.8-.7h.8v1.5h-.8zM80 62.5l.8-.8h.7v1.5h-.7zM167.6 62.5l.8-.8h.8v1.5h-.8zM48 98.5h.8l.7 .8-.7 .8h-.8zM48 96h.8l.7 .8-.7 .7h-.8zM135.6 98.5h.8l.8 .8-.8 .8h-.8zM135.6 96h.8l.8 .8-.8 .7h-.8zM252.2 85.8h.8v1.6h-.8l-.7-.8zM252.2 89.7h.8v1.5h-.8l-.7-.8zM252.2 92.2h.8v1.5h-.8l-.7-.7zM252.2 96h.8v1.5h-.8l-.7-.7z"/>
<path d="M252.2 98.5h.8v1.6h-.8l-.7-.8zM48 103.6h.8l.7 .8-.7 .8h-.8zM48 106.2h.8l.7 .7-.7 .8h-.8zM48 101.1h.8l.7 .7-.7 .8h-.8zM96 101.1h.8v1.5h-.8l-.8-.8zM135.6 103.6h.8l.8 .8-.8 .8h-.8zM135.6 106.2h.8l.8 .7-.8 .8h-.8zM135.6 101.1h.8l.8 .7-.8 .8h-.8zM183.6 101.1h.8v1.5h-.8l-.7-.8zM80 127.2l.8-.7h.7v1.5h-.7zM80.8 129h.7v1.6h-.7l-.8-.8zM168.4 126.5h.8v1.5h-.8l-.8-.8z"/>
<path d="M168.4 129h.8v1.6h-.8l-.8-.8z"/>
</g>
<g fill="none" stroke="#008400" stroke-width=".18">
<path d="M48.3 29.5h8.8M48.3 32h8.8M48.3 37.1h8.8M48.3 34.5h8.8M48.3 39.6h8.8M69.8 29.5h22.9M69.8 32h22.9M69.8 37.1h22.9M69.8 34.5h25.4M69.8 39.6h22.9M137.2 29.5h7.6M137.2 32h7.6"/>
<path d="M137.2 37.1h7.6M137.2 34.5h7.6M137.2 39.6h7.6M157.5 29.5h22.8M157.5 32h22.8M157.5 37.1h22.8M157.5 34.5h25.4M157.5 39.6h22.8M30.5 44.7h26.6M38.1 49.8h19M55.9 59.9h1.2M57.1 57.4h-1.2v7.6h1.2"/>
<path d="M69.8 54.9h22.9M69.8 44.7h1.3M69.8 49.8h1.3M69.8 59.9h10.2M69.8 57.4h3.9M69.8 42.2h1.3v10.1h-1.3M69.8 47.2h3.9M109.2 54.9h-7.6v2.5M118.1 44.7h26.7M125.7 49.8h19.1M143.5 59.9h1.3M144.8 57.4h-1.3v7.6h1.3"/>
<path d="M157.5 54.9h22.8M157.5 44.7h1.2M157.5 49.8h1.2M157.5 59.9h10.1M157.5 57.4h3.8M157.5 42.2h1.2v10.1h-1.2M157.5 47.2h3.8M199.4 54.9h-7.6v2.5M44.4 67.6h12.7M54.6 61.2h1.3M54.6 73.9h1.3M55.9 72.6h1.2"/>
<path d="M55.9 75.2h1.2M55.9 62.5h1.2M57.1 70.1h-1.2v7.6h1.2M69.8 67.6h38.1v2.5M69.8 75.2h10.2v2.5h3.8M69.8 62.5h10.2M69.8 65h3.9M69.8 70.1h3.9M69.8 77.7h3.9M83.8 70.1h-3.8v2.5h-10.2M101.6 65v5.1M101.6 77.7v2.6"/>
<path d="M107.9 77.7v2.6M132.1 67.6h12.7M142.2 61.2h1.3M142.2 73.9h1.3M143.5 72.6h1.3M143.5 75.2h1.3M143.5 62.5h1.3M144.8 70.1h-1.3v7.6h1.3M157.5 67.6h40.6v2.5M157.5 75.2h10.1v2.5h3.8M157.5 62.5h10.1M157.5 65h3.8"/>
<path d="M157.5 70.1h3.8M157.5 77.7h3.8M171.4 70.1h-3.8v2.5h-10.1M191.8 65v5.1M191.8 77.7v2.6M198.1 77.7v2.6M49.5 96.8h7.6M49.5 99.3h7.6M63.5 84.1v1.2M69.8 96.8h22.9M69.8 99.3h22.9M137.2 96.8h7.6"/>
<path d="M137.2 99.3h7.6M151.1 84.1v1.2M157.5 96.8h22.8M157.5 99.3h22.8M228.6 96.8h22.9M228.6 99.3h22.9M228.6 90.4h22.9M228.6 93h22.9M228.6 86.6h22.9M30.5 112h26.6M38.1 117.1h19M49.5 104.4h7.6"/>
<path d="M49.5 101.8h7.6M49.5 106.9h7.6M69.8 109.5h1.3v10.1h-1.3M69.8 104.4h22.9M69.8 101.8h25.4M69.8 106.9h22.9M69.8 112h1.3M69.8 117.1h1.3M69.8 114.5h3.9M109.2 119.6h-7.6v5.1M118.1 112h26.7M125.7 117.1h19.1"/>
<path d="M137.2 104.4h7.6M137.2 101.8h7.6M137.2 106.9h7.6M157.5 104.4h22.8M157.5 101.8h25.4M157.5 106.9h22.8M157.5 112h1.2M157.5 117.1h1.2M157.5 109.5h1.2v10.1h-1.2M157.5 114.5h3.8M199.4 119.6h-7.6v5.1M44.4 134.9h12.7"/>
<path d="M54.6 128.5h1.3M55.9 127.2h1.2M55.9 129.8h1.2M55.9 139.9h1.2M57.1 124.7h-1.2v7.6h1.2M57.1 137.4h-1.2v7.6h1.2M69.8 134.9h38.1v2.5M69.8 122.2h22.9M69.8 127.2h10.2M69.8 129.8h10.2M69.8 124.7h3.9M69.8 132.3h3.9"/>
<path d="M69.8 137.4h3.9M83.8 137.4h-3.8v2.5h-10.2M101.6 132.3v5.1M132.1 134.9h12.7M142.2 128.5h1.3M143.5 127.2h1.3M143.5 129.8h1.3M143.5 139.9h1.3M144.8 124.7h-1.3v7.6h1.3M144.8 137.4h-1.3v7.6h1.3M157.5 122.2h22.8M157.5 127.2h10.1"/>
<path d="M157.5 129.8h10.1M157.5 134.9h40.6v2.5M157.5 124.7h3.8M157.5 132.3h3.8M157.5 137.4h3.8M171.4 137.4h-3.8v2.5h-10.1M191.8 132.3v5.1M54.6 141.2h1.3M55.9 142.5h1.2M63.5 151.4v1.2M69.8 142.5h10.2v2.5h3.8M69.8 145h3.9"/>
<path d="M101.6 145v2.6M107.9 145v2.6M142.2 141.2h1.3M143.5 142.5h1.3M151.1 151.4v1.2M157.5 142.5h10.1v2.5h3.8M157.5 145h3.8M191.8 145v2.6M198.1 145v2.6"/>
</g>
<g fill="#008400" stroke="#008400" stroke-width=".25">
<circle cx="55.9" cy="61.2" r=".51"/>
<circle cx="55.9" cy="62.5" r=".51"/>
<circle cx="55.9" cy="59.9" r=".51"/>
<circle cx="55.9" cy="73.9" r=".51"/>
<circle cx="55.9" cy="75.2" r=".51"/>
<circle cx="55.9" cy="72.6" r=".51"/>
<circle cx="71.1" cy="44.7" r=".51"/>
<circle cx="71.1" cy="49.8" r=".51"/>
<circle cx="71.1" cy="52.3" r=".51"/>
<circle cx="71.1" cy="47.2" r=".51"/>
<circle cx="101.6" cy="67.6" r=".51"/>
<circle cx="55.9" cy="128.5" r=".51"/>
<circle cx="55.9" cy="129.8" r=".51"/>
<circle cx="55.9" cy="127.2" r=".51"/>
<circle cx="55.9" cy="141.2" r=".51"/>
<circle cx="55.9" cy="142.5" r=".51"/>
<circle cx="55.9" cy="139.9" r=".51"/>
<circle cx="71.1" cy="112" r=".51"/>
<circle cx="71.1" cy="117.1" r=".51"/>
<circle cx="71.1" cy="119.6" r=".51"/>
<circle cx="71.1" cy="114.5" r=".51"/>
<circle cx="101.6" cy="134.9" r=".51"/>
<circle cx="143.5" cy="61.2" r=".51"/>
<circle cx="143.5" cy="62.5" r=".51"/>
<circle cx="143.5" cy="59.9" r=".51"/>
<circle cx="143.5" cy="73.9" r=".51"/>
<circle cx="143.5" cy="75.2" r=".51"/>
<circle cx="143.5" cy="72.6" r=".51"/>
<circle cx="158.8" cy="44.7" r=".51"/>
<circle cx="158.8" cy="49.8" r=".51"/>
<circle cx="158.8" cy="52.3" r=".51"/>
<circle cx="158.8" cy="47.2" r=".51"/>
<circle cx="191.8" cy="67.6" r=".51"/>
<circle cx="143.5" cy="128.5" r=".51"/>
<circle cx="143.5" cy="129.8" r=".51"/>
<circle cx="143.5" cy="127.2" r=".51"/>
<circle cx="143.5" cy="141.2" r=".51"/>
<circle cx="143.5" cy="142.5" r=".51"/>
<circle cx="143.5" cy="139.9" r=".51"/>
<circle cx="158.8" cy="112" r=".51"/>
<circle cx="158.8" cy="117.1" r=".51"/>
<circle cx="158.8" cy="119.6" r=".51"/>
<circle cx="158.8" cy="114.5" r=".51"/>
<circle cx="191.8" cy="134.9" r=".51"/>
</g>
<use href="#words"/>
</svg>
